VERSION 5.7 ;
  NOWIREEXTENSIONATPIN ON ;
  DIVIDERCHAR "/" ;
  BUSBITCHARS "[]" ;
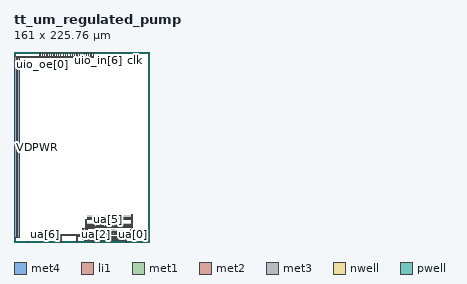
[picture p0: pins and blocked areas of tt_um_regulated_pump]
MACRO tt_um_regulated_pump
  CLASS BLOCK ;
  FOREIGN tt_um_regulated_pump ;
  ORIGIN 0.000 0.000 ;
  SIZE 161.000 BY 225.760 ;
  PIN clk
    DIRECTION INPUT ;
    USE SIGNAL ;
    PORT
      LAYER met4 ;
        RECT 143.830 224.760 144.130 225.760 ;
    END
  END clk
  PIN ena
    DIRECTION INPUT ;
    USE SIGNAL ;
    PORT
      LAYER met4 ;
        RECT 146.590 224.760 146.890 225.760 ;
    END
  END ena
  PIN rst_n
    DIRECTION INPUT ;
    USE SIGNAL ;
    PORT
      LAYER met4 ;
        RECT 141.070 224.760 141.370 225.760 ;
    END
  END rst_n
  PIN ua[0]
    DIRECTION INOUT ;
    USE SIGNAL ;
    PORT
      LAYER met4 ;
        RECT 151.810 0.000 152.710 1.000 ;
    END
  END ua[0]
  PIN ua[1]
    DIRECTION INOUT ;
    USE SIGNAL ;
    ANTENNAGATEAREA 3.960000 ;
    PORT
      LAYER li1 ;
        RECT 109.245 10.075 114.685 10.315 ;
      LAYER met1 ;
        RECT 108.300 10.315 108.740 10.410 ;
        RECT 108.300 10.065 109.540 10.315 ;
        RECT 108.300 9.970 108.740 10.065 ;
      LAYER met2 ;
        RECT 83.580 2.180 84.020 13.020 ;
        RECT 108.300 9.970 108.740 13.020 ;
        RECT 132.720 0.280 133.160 2.620 ;
      LAYER met3 ;
        RECT 83.580 12.580 108.760 13.020 ;
        RECT 83.580 2.180 133.160 2.620 ;
        RECT 132.670 0.230 133.210 0.770 ;
      LAYER met4 ;
        RECT 132.490 0.000 133.390 1.000 ;
    END
  END ua[1]
  PIN ua[2]
    DIRECTION INOUT ;
    USE SIGNAL ;
    ANTENNAGATEAREA 7.920000 ;
    PORT
      LAYER li1 ;
        RECT 88.085 10.075 93.525 10.315 ;
        RECT 98.665 10.075 104.105 10.315 ;
      LAYER met1 ;
        RECT 87.140 10.315 87.580 10.410 ;
        RECT 97.720 10.315 98.160 10.410 ;
        RECT 87.140 10.065 88.380 10.315 ;
        RECT 97.720 10.065 98.960 10.315 ;
        RECT 87.140 9.970 87.580 10.065 ;
        RECT 97.720 9.970 98.160 10.065 ;
      LAYER met2 ;
        RECT 81.580 3.380 82.020 16.220 ;
        RECT 87.140 9.970 87.580 16.220 ;
        RECT 97.720 15.780 98.180 16.220 ;
        RECT 97.720 9.970 98.160 15.780 ;
        RECT 113.400 0.280 113.840 3.820 ;
      LAYER met3 ;
        RECT 81.580 15.780 98.180 16.220 ;
        RECT 81.580 3.380 113.840 3.820 ;
        RECT 113.350 0.230 113.890 0.770 ;
      LAYER met4 ;
        RECT 113.170 0.000 114.070 1.000 ;
    END
  END ua[2]
  PIN ua[3]
    DIRECTION INOUT ;
    USE SIGNAL ;
    ANTENNADIFFAREA 3.564000 ;
    PORT
      LAYER li1 ;
        RECT 130.900 10.665 131.230 11.465 ;
        RECT 131.740 10.665 132.070 11.465 ;
        RECT 132.580 10.665 132.910 11.465 ;
        RECT 133.420 10.665 133.750 11.465 ;
        RECT 134.260 10.665 134.590 11.465 ;
        RECT 135.100 10.665 135.430 11.465 ;
        RECT 135.940 10.665 136.270 11.465 ;
        RECT 136.780 10.665 137.110 11.465 ;
        RECT 130.900 10.495 137.110 10.665 ;
        RECT 136.780 9.905 137.110 10.495 ;
        RECT 130.900 9.715 137.110 9.905 ;
        RECT 130.900 9.255 131.230 9.715 ;
        RECT 131.740 9.255 132.070 9.715 ;
        RECT 132.580 9.255 132.910 9.715 ;
        RECT 133.420 9.255 133.750 9.715 ;
        RECT 134.260 9.255 134.590 9.715 ;
        RECT 135.100 9.255 135.430 9.715 ;
        RECT 135.940 9.255 136.270 9.715 ;
        RECT 136.780 9.255 137.110 9.715 ;
      LAYER met1 ;
        RECT 138.560 10.315 139.000 10.410 ;
        RECT 136.840 10.065 139.000 10.315 ;
        RECT 138.560 9.970 139.000 10.065 ;
      LAYER met2 ;
        RECT 138.560 9.970 139.000 14.620 ;
        RECT 94.080 0.280 94.520 5.020 ;
        RECT 142.120 4.580 142.560 14.620 ;
      LAYER met3 ;
        RECT 138.540 14.180 142.560 14.620 ;
        RECT 94.080 4.580 142.560 5.020 ;
        RECT 94.030 0.230 94.570 0.770 ;
      LAYER met4 ;
        RECT 93.850 0.000 94.750 1.000 ;
    END
  END ua[3]
  PIN ua[4]
    DIRECTION INOUT ;
    USE SIGNAL ;
    ANTENNADIFFAREA 38.381248 ;
    PORT
      LAYER nwell ;
        RECT 87.810 27.785 96.010 29.390 ;
        RECT 98.390 27.785 106.590 29.390 ;
        RECT 108.970 27.785 117.170 29.390 ;
        RECT 119.550 27.785 127.750 29.390 ;
        RECT 130.130 27.785 138.330 29.390 ;
        RECT 87.810 19.045 96.010 20.650 ;
        RECT 98.390 19.045 106.590 20.650 ;
        RECT 108.970 19.045 117.170 20.650 ;
        RECT 119.550 19.045 127.750 20.650 ;
        RECT 130.130 19.045 138.330 20.650 ;
        RECT 87.810 10.305 96.010 11.910 ;
        RECT 98.390 10.305 106.590 11.910 ;
        RECT 108.970 10.305 117.170 11.910 ;
        RECT 119.550 10.305 127.750 11.910 ;
        RECT 130.130 10.305 138.330 11.910 ;
      LAYER li1 ;
        RECT 88.000 29.115 95.820 29.285 ;
        RECT 98.580 29.115 106.400 29.285 ;
        RECT 109.160 29.115 116.980 29.285 ;
        RECT 119.740 29.115 127.560 29.285 ;
        RECT 130.320 29.115 138.140 29.285 ;
        RECT 88.200 27.965 88.410 29.115 ;
        RECT 89.080 28.315 89.250 29.115 ;
        RECT 89.920 28.315 90.090 29.115 ;
        RECT 90.760 28.315 90.930 29.115 ;
        RECT 91.600 28.315 91.770 29.115 ;
        RECT 92.440 28.315 92.610 29.115 ;
        RECT 93.280 28.315 93.450 29.115 ;
        RECT 94.120 28.315 94.290 29.115 ;
        RECT 94.960 28.315 95.170 29.115 ;
        RECT 95.445 27.950 95.735 29.115 ;
        RECT 98.780 27.965 98.990 29.115 ;
        RECT 99.660 28.315 99.830 29.115 ;
        RECT 100.500 28.315 100.670 29.115 ;
        RECT 101.340 28.315 101.510 29.115 ;
        RECT 102.180 28.315 102.350 29.115 ;
        RECT 103.020 28.315 103.190 29.115 ;
        RECT 103.860 28.315 104.030 29.115 ;
        RECT 104.700 28.315 104.870 29.115 ;
        RECT 105.540 28.315 105.750 29.115 ;
        RECT 106.025 27.950 106.315 29.115 ;
        RECT 109.360 27.965 109.570 29.115 ;
        RECT 110.240 28.315 110.410 29.115 ;
        RECT 111.080 28.315 111.250 29.115 ;
        RECT 111.920 28.315 112.090 29.115 ;
        RECT 112.760 28.315 112.930 29.115 ;
        RECT 113.600 28.315 113.770 29.115 ;
        RECT 114.440 28.315 114.610 29.115 ;
        RECT 115.280 28.315 115.450 29.115 ;
        RECT 116.120 28.315 116.330 29.115 ;
        RECT 116.605 27.950 116.895 29.115 ;
        RECT 119.940 27.965 120.150 29.115 ;
        RECT 120.820 28.315 120.990 29.115 ;
        RECT 121.660 28.315 121.830 29.115 ;
        RECT 122.500 28.315 122.670 29.115 ;
        RECT 123.340 28.315 123.510 29.115 ;
        RECT 124.180 28.315 124.350 29.115 ;
        RECT 125.020 28.315 125.190 29.115 ;
        RECT 125.860 28.315 126.030 29.115 ;
        RECT 126.700 28.315 126.910 29.115 ;
        RECT 127.185 27.950 127.475 29.115 ;
        RECT 130.520 27.965 130.730 29.115 ;
        RECT 131.400 28.315 131.570 29.115 ;
        RECT 132.240 28.315 132.410 29.115 ;
        RECT 133.080 28.315 133.250 29.115 ;
        RECT 133.920 28.315 134.090 29.115 ;
        RECT 134.760 28.315 134.930 29.115 ;
        RECT 135.600 28.315 135.770 29.115 ;
        RECT 136.440 28.315 136.610 29.115 ;
        RECT 137.280 28.315 137.490 29.115 ;
        RECT 137.765 27.950 138.055 29.115 ;
        RECT 88.000 20.375 95.820 20.545 ;
        RECT 98.580 20.375 106.400 20.545 ;
        RECT 109.160 20.375 116.980 20.545 ;
        RECT 119.740 20.375 127.560 20.545 ;
        RECT 130.320 20.375 138.140 20.545 ;
        RECT 88.200 19.225 88.410 20.375 ;
        RECT 89.080 19.575 89.250 20.375 ;
        RECT 89.920 19.575 90.090 20.375 ;
        RECT 90.760 19.575 90.930 20.375 ;
        RECT 91.600 19.575 91.770 20.375 ;
        RECT 92.440 19.575 92.610 20.375 ;
        RECT 93.280 19.575 93.450 20.375 ;
        RECT 94.120 19.575 94.290 20.375 ;
        RECT 94.960 19.575 95.170 20.375 ;
        RECT 95.445 19.210 95.735 20.375 ;
        RECT 98.780 19.225 98.990 20.375 ;
        RECT 99.660 19.575 99.830 20.375 ;
        RECT 100.500 19.575 100.670 20.375 ;
        RECT 101.340 19.575 101.510 20.375 ;
        RECT 102.180 19.575 102.350 20.375 ;
        RECT 103.020 19.575 103.190 20.375 ;
        RECT 103.860 19.575 104.030 20.375 ;
        RECT 104.700 19.575 104.870 20.375 ;
        RECT 105.540 19.575 105.750 20.375 ;
        RECT 106.025 19.210 106.315 20.375 ;
        RECT 109.360 19.225 109.570 20.375 ;
        RECT 110.240 19.575 110.410 20.375 ;
        RECT 111.080 19.575 111.250 20.375 ;
        RECT 111.920 19.575 112.090 20.375 ;
        RECT 112.760 19.575 112.930 20.375 ;
        RECT 113.600 19.575 113.770 20.375 ;
        RECT 114.440 19.575 114.610 20.375 ;
        RECT 115.280 19.575 115.450 20.375 ;
        RECT 116.120 19.575 116.330 20.375 ;
        RECT 116.605 19.210 116.895 20.375 ;
        RECT 119.940 19.225 120.150 20.375 ;
        RECT 120.820 19.575 120.990 20.375 ;
        RECT 121.660 19.575 121.830 20.375 ;
        RECT 122.500 19.575 122.670 20.375 ;
        RECT 123.340 19.575 123.510 20.375 ;
        RECT 124.180 19.575 124.350 20.375 ;
        RECT 125.020 19.575 125.190 20.375 ;
        RECT 125.860 19.575 126.030 20.375 ;
        RECT 126.700 19.575 126.910 20.375 ;
        RECT 127.185 19.210 127.475 20.375 ;
        RECT 130.520 19.225 130.730 20.375 ;
        RECT 131.400 19.575 131.570 20.375 ;
        RECT 132.240 19.575 132.410 20.375 ;
        RECT 133.080 19.575 133.250 20.375 ;
        RECT 133.920 19.575 134.090 20.375 ;
        RECT 134.760 19.575 134.930 20.375 ;
        RECT 135.600 19.575 135.770 20.375 ;
        RECT 136.440 19.575 136.610 20.375 ;
        RECT 137.280 19.575 137.490 20.375 ;
        RECT 137.765 19.210 138.055 20.375 ;
        RECT 88.000 11.635 95.820 11.805 ;
        RECT 98.580 11.635 106.400 11.805 ;
        RECT 109.160 11.635 116.980 11.805 ;
        RECT 119.740 11.635 127.560 11.805 ;
        RECT 130.320 11.635 138.140 11.805 ;
        RECT 88.200 10.485 88.410 11.635 ;
        RECT 89.080 10.835 89.250 11.635 ;
        RECT 89.920 10.835 90.090 11.635 ;
        RECT 90.760 10.835 90.930 11.635 ;
        RECT 91.600 10.835 91.770 11.635 ;
        RECT 92.440 10.835 92.610 11.635 ;
        RECT 93.280 10.835 93.450 11.635 ;
        RECT 94.120 10.835 94.290 11.635 ;
        RECT 94.960 10.835 95.170 11.635 ;
        RECT 95.445 10.470 95.735 11.635 ;
        RECT 98.780 10.485 98.990 11.635 ;
        RECT 99.660 10.835 99.830 11.635 ;
        RECT 100.500 10.835 100.670 11.635 ;
        RECT 101.340 10.835 101.510 11.635 ;
        RECT 102.180 10.835 102.350 11.635 ;
        RECT 103.020 10.835 103.190 11.635 ;
        RECT 103.860 10.835 104.030 11.635 ;
        RECT 104.700 10.835 104.870 11.635 ;
        RECT 105.540 10.835 105.750 11.635 ;
        RECT 106.025 10.470 106.315 11.635 ;
        RECT 109.360 10.485 109.570 11.635 ;
        RECT 110.240 10.835 110.410 11.635 ;
        RECT 111.080 10.835 111.250 11.635 ;
        RECT 111.920 10.835 112.090 11.635 ;
        RECT 112.760 10.835 112.930 11.635 ;
        RECT 113.600 10.835 113.770 11.635 ;
        RECT 114.440 10.835 114.610 11.635 ;
        RECT 115.280 10.835 115.450 11.635 ;
        RECT 116.120 10.835 116.330 11.635 ;
        RECT 116.605 10.470 116.895 11.635 ;
        RECT 119.940 10.485 120.150 11.635 ;
        RECT 120.820 10.835 120.990 11.635 ;
        RECT 121.660 10.835 121.830 11.635 ;
        RECT 122.500 10.835 122.670 11.635 ;
        RECT 123.340 10.835 123.510 11.635 ;
        RECT 124.180 10.835 124.350 11.635 ;
        RECT 125.020 10.835 125.190 11.635 ;
        RECT 125.860 10.835 126.030 11.635 ;
        RECT 126.700 10.835 126.910 11.635 ;
        RECT 127.185 10.470 127.475 11.635 ;
        RECT 130.520 10.485 130.730 11.635 ;
        RECT 131.400 10.835 131.570 11.635 ;
        RECT 132.240 10.835 132.410 11.635 ;
        RECT 133.080 10.835 133.250 11.635 ;
        RECT 133.920 10.835 134.090 11.635 ;
        RECT 134.760 10.835 134.930 11.635 ;
        RECT 135.600 10.835 135.770 11.635 ;
        RECT 136.440 10.835 136.610 11.635 ;
        RECT 137.280 10.835 137.490 11.635 ;
        RECT 137.765 10.470 138.055 11.635 ;
      LAYER met1 ;
        RECT 88.000 28.960 140.840 29.440 ;
        RECT 88.000 20.220 140.840 20.700 ;
        RECT 88.000 11.480 140.840 11.960 ;
      LAYER met2 ;
        RECT 139.840 11.480 140.840 32.320 ;
        RECT 140.090 6.250 140.590 11.480 ;
      LAYER met3 ;
        RECT 74.730 6.250 140.590 6.750 ;
        RECT 74.730 0.250 75.230 6.250 ;
      LAYER met4 ;
        RECT 74.530 0.000 75.430 1.000 ;
    END
  END ua[4]
  PIN ua[5]
    DIRECTION INOUT ;
    USE SIGNAL ;
    ANTENNADIFFAREA 24.836250 ;
    PORT
      LAYER pwell ;
        RECT 95.375 26.670 95.805 27.455 ;
        RECT 105.955 26.670 106.385 27.455 ;
        RECT 116.535 26.670 116.965 27.455 ;
        RECT 127.115 26.670 127.545 27.455 ;
        RECT 137.695 26.670 138.125 27.455 ;
        RECT 95.375 17.930 95.805 18.715 ;
        RECT 105.955 17.930 106.385 18.715 ;
        RECT 116.535 17.930 116.965 18.715 ;
        RECT 127.115 17.930 127.545 18.715 ;
        RECT 137.695 17.930 138.125 18.715 ;
        RECT 95.375 9.190 95.805 9.975 ;
        RECT 105.955 9.190 106.385 9.975 ;
        RECT 116.535 9.190 116.965 9.975 ;
        RECT 127.115 9.190 127.545 9.975 ;
        RECT 137.695 9.190 138.125 9.975 ;
      LAYER li1 ;
        RECT 88.180 26.565 88.410 27.365 ;
        RECT 89.080 26.565 89.250 27.025 ;
        RECT 89.920 26.565 90.090 27.025 ;
        RECT 90.760 26.565 90.930 27.025 ;
        RECT 91.600 26.565 91.770 27.025 ;
        RECT 92.440 26.565 92.610 27.025 ;
        RECT 93.280 26.565 93.450 27.025 ;
        RECT 94.120 26.565 94.290 27.025 ;
        RECT 94.960 26.565 95.170 27.365 ;
        RECT 95.445 26.565 95.735 27.290 ;
        RECT 98.760 26.565 98.990 27.365 ;
        RECT 99.660 26.565 99.830 27.025 ;
        RECT 100.500 26.565 100.670 27.025 ;
        RECT 101.340 26.565 101.510 27.025 ;
        RECT 102.180 26.565 102.350 27.025 ;
        RECT 103.020 26.565 103.190 27.025 ;
        RECT 103.860 26.565 104.030 27.025 ;
        RECT 104.700 26.565 104.870 27.025 ;
        RECT 105.540 26.565 105.750 27.365 ;
        RECT 106.025 26.565 106.315 27.290 ;
        RECT 109.340 26.565 109.570 27.365 ;
        RECT 110.240 26.565 110.410 27.025 ;
        RECT 111.080 26.565 111.250 27.025 ;
        RECT 111.920 26.565 112.090 27.025 ;
        RECT 112.760 26.565 112.930 27.025 ;
        RECT 113.600 26.565 113.770 27.025 ;
        RECT 114.440 26.565 114.610 27.025 ;
        RECT 115.280 26.565 115.450 27.025 ;
        RECT 116.120 26.565 116.330 27.365 ;
        RECT 116.605 26.565 116.895 27.290 ;
        RECT 119.920 26.565 120.150 27.365 ;
        RECT 120.820 26.565 120.990 27.025 ;
        RECT 121.660 26.565 121.830 27.025 ;
        RECT 122.500 26.565 122.670 27.025 ;
        RECT 123.340 26.565 123.510 27.025 ;
        RECT 124.180 26.565 124.350 27.025 ;
        RECT 125.020 26.565 125.190 27.025 ;
        RECT 125.860 26.565 126.030 27.025 ;
        RECT 126.700 26.565 126.910 27.365 ;
        RECT 127.185 26.565 127.475 27.290 ;
        RECT 130.500 26.565 130.730 27.365 ;
        RECT 131.400 26.565 131.570 27.025 ;
        RECT 132.240 26.565 132.410 27.025 ;
        RECT 133.080 26.565 133.250 27.025 ;
        RECT 133.920 26.565 134.090 27.025 ;
        RECT 134.760 26.565 134.930 27.025 ;
        RECT 135.600 26.565 135.770 27.025 ;
        RECT 136.440 26.565 136.610 27.025 ;
        RECT 137.280 26.565 137.490 27.365 ;
        RECT 137.765 26.565 138.055 27.290 ;
        RECT 88.000 26.395 95.820 26.565 ;
        RECT 98.580 26.395 106.400 26.565 ;
        RECT 109.160 26.395 116.980 26.565 ;
        RECT 119.740 26.395 127.560 26.565 ;
        RECT 130.320 26.395 138.140 26.565 ;
        RECT 88.180 17.825 88.410 18.625 ;
        RECT 89.080 17.825 89.250 18.285 ;
        RECT 89.920 17.825 90.090 18.285 ;
        RECT 90.760 17.825 90.930 18.285 ;
        RECT 91.600 17.825 91.770 18.285 ;
        RECT 92.440 17.825 92.610 18.285 ;
        RECT 93.280 17.825 93.450 18.285 ;
        RECT 94.120 17.825 94.290 18.285 ;
        RECT 94.960 17.825 95.170 18.625 ;
        RECT 95.445 17.825 95.735 18.550 ;
        RECT 98.760 17.825 98.990 18.625 ;
        RECT 99.660 17.825 99.830 18.285 ;
        RECT 100.500 17.825 100.670 18.285 ;
        RECT 101.340 17.825 101.510 18.285 ;
        RECT 102.180 17.825 102.350 18.285 ;
        RECT 103.020 17.825 103.190 18.285 ;
        RECT 103.860 17.825 104.030 18.285 ;
        RECT 104.700 17.825 104.870 18.285 ;
        RECT 105.540 17.825 105.750 18.625 ;
        RECT 106.025 17.825 106.315 18.550 ;
        RECT 109.340 17.825 109.570 18.625 ;
        RECT 110.240 17.825 110.410 18.285 ;
        RECT 111.080 17.825 111.250 18.285 ;
        RECT 111.920 17.825 112.090 18.285 ;
        RECT 112.760 17.825 112.930 18.285 ;
        RECT 113.600 17.825 113.770 18.285 ;
        RECT 114.440 17.825 114.610 18.285 ;
        RECT 115.280 17.825 115.450 18.285 ;
        RECT 116.120 17.825 116.330 18.625 ;
        RECT 116.605 17.825 116.895 18.550 ;
        RECT 119.920 17.825 120.150 18.625 ;
        RECT 120.820 17.825 120.990 18.285 ;
        RECT 121.660 17.825 121.830 18.285 ;
        RECT 122.500 17.825 122.670 18.285 ;
        RECT 123.340 17.825 123.510 18.285 ;
        RECT 124.180 17.825 124.350 18.285 ;
        RECT 125.020 17.825 125.190 18.285 ;
        RECT 125.860 17.825 126.030 18.285 ;
        RECT 126.700 17.825 126.910 18.625 ;
        RECT 127.185 17.825 127.475 18.550 ;
        RECT 130.500 17.825 130.730 18.625 ;
        RECT 131.400 17.825 131.570 18.285 ;
        RECT 132.240 17.825 132.410 18.285 ;
        RECT 133.080 17.825 133.250 18.285 ;
        RECT 133.920 17.825 134.090 18.285 ;
        RECT 134.760 17.825 134.930 18.285 ;
        RECT 135.600 17.825 135.770 18.285 ;
        RECT 136.440 17.825 136.610 18.285 ;
        RECT 137.280 17.825 137.490 18.625 ;
        RECT 137.765 17.825 138.055 18.550 ;
        RECT 88.000 17.655 95.820 17.825 ;
        RECT 98.580 17.655 106.400 17.825 ;
        RECT 109.160 17.655 116.980 17.825 ;
        RECT 119.740 17.655 127.560 17.825 ;
        RECT 130.320 17.655 138.140 17.825 ;
        RECT 88.180 9.085 88.410 9.885 ;
        RECT 89.080 9.085 89.250 9.545 ;
        RECT 89.920 9.085 90.090 9.545 ;
        RECT 90.760 9.085 90.930 9.545 ;
        RECT 91.600 9.085 91.770 9.545 ;
        RECT 92.440 9.085 92.610 9.545 ;
        RECT 93.280 9.085 93.450 9.545 ;
        RECT 94.120 9.085 94.290 9.545 ;
        RECT 94.960 9.085 95.170 9.885 ;
        RECT 95.445 9.085 95.735 9.810 ;
        RECT 98.760 9.085 98.990 9.885 ;
        RECT 99.660 9.085 99.830 9.545 ;
        RECT 100.500 9.085 100.670 9.545 ;
        RECT 101.340 9.085 101.510 9.545 ;
        RECT 102.180 9.085 102.350 9.545 ;
        RECT 103.020 9.085 103.190 9.545 ;
        RECT 103.860 9.085 104.030 9.545 ;
        RECT 104.700 9.085 104.870 9.545 ;
        RECT 105.540 9.085 105.750 9.885 ;
        RECT 106.025 9.085 106.315 9.810 ;
        RECT 109.340 9.085 109.570 9.885 ;
        RECT 110.240 9.085 110.410 9.545 ;
        RECT 111.080 9.085 111.250 9.545 ;
        RECT 111.920 9.085 112.090 9.545 ;
        RECT 112.760 9.085 112.930 9.545 ;
        RECT 113.600 9.085 113.770 9.545 ;
        RECT 114.440 9.085 114.610 9.545 ;
        RECT 115.280 9.085 115.450 9.545 ;
        RECT 116.120 9.085 116.330 9.885 ;
        RECT 116.605 9.085 116.895 9.810 ;
        RECT 119.920 9.085 120.150 9.885 ;
        RECT 120.820 9.085 120.990 9.545 ;
        RECT 121.660 9.085 121.830 9.545 ;
        RECT 122.500 9.085 122.670 9.545 ;
        RECT 123.340 9.085 123.510 9.545 ;
        RECT 124.180 9.085 124.350 9.545 ;
        RECT 125.020 9.085 125.190 9.545 ;
        RECT 125.860 9.085 126.030 9.545 ;
        RECT 126.700 9.085 126.910 9.885 ;
        RECT 127.185 9.085 127.475 9.810 ;
        RECT 130.500 9.085 130.730 9.885 ;
        RECT 131.400 9.085 131.570 9.545 ;
        RECT 132.240 9.085 132.410 9.545 ;
        RECT 133.080 9.085 133.250 9.545 ;
        RECT 133.920 9.085 134.090 9.545 ;
        RECT 134.760 9.085 134.930 9.545 ;
        RECT 135.600 9.085 135.770 9.545 ;
        RECT 136.440 9.085 136.610 9.545 ;
        RECT 137.280 9.085 137.490 9.885 ;
        RECT 137.765 9.085 138.055 9.810 ;
        RECT 88.000 8.915 95.820 9.085 ;
        RECT 98.580 8.915 106.400 9.085 ;
        RECT 109.160 8.915 116.980 9.085 ;
        RECT 119.740 8.915 127.560 9.085 ;
        RECT 130.320 8.915 138.140 9.085 ;
      LAYER met1 ;
        RECT 85.300 26.240 138.140 26.720 ;
        RECT 85.300 17.500 138.140 17.980 ;
        RECT 85.300 8.760 138.140 9.240 ;
      LAYER met2 ;
        RECT 85.300 8.260 86.300 26.720 ;
        RECT 85.550 8.250 86.050 8.260 ;
      LAYER met3 ;
        RECT 55.410 8.250 86.050 8.750 ;
        RECT 55.410 0.250 55.910 8.250 ;
      LAYER met4 ;
        RECT 55.210 0.000 56.110 1.000 ;
    END
  END ua[5]
  PIN ua[6]
    DIRECTION INOUT ;
    USE SIGNAL ;
    PORT
      LAYER met4 ;
        RECT 35.890 0.000 36.790 1.000 ;
    END
  END ua[6]
  PIN ua[7]
    DIRECTION INOUT ;
    USE SIGNAL ;
    PORT
      LAYER met4 ;
        RECT 16.570 0.000 17.470 1.000 ;
    END
  END ua[7]
  PIN ui_in[0]
    DIRECTION INPUT ;
    USE SIGNAL ;
    PORT
      LAYER met4 ;
        RECT 138.310 224.760 138.610 225.760 ;
    END
  END ui_in[0]
  PIN ui_in[1]
    DIRECTION INPUT ;
    USE SIGNAL ;
    PORT
      LAYER met4 ;
        RECT 135.550 224.760 135.850 225.760 ;
    END
  END ui_in[1]
  PIN ui_in[2]
    DIRECTION INPUT ;
    USE SIGNAL ;
    PORT
      LAYER met4 ;
        RECT 132.790 224.760 133.090 225.760 ;
    END
  END ui_in[2]
  PIN ui_in[3]
    DIRECTION INPUT ;
    USE SIGNAL ;
    PORT
      LAYER met4 ;
        RECT 130.030 224.760 130.330 225.760 ;
    END
  END ui_in[3]
  PIN ui_in[4]
    DIRECTION INPUT ;
    USE SIGNAL ;
    PORT
      LAYER met4 ;
        RECT 127.270 224.760 127.570 225.760 ;
    END
  END ui_in[4]
  PIN ui_in[5]
    DIRECTION INPUT ;
    USE SIGNAL ;
    PORT
      LAYER met4 ;
        RECT 124.510 224.760 124.810 225.760 ;
    END
  END ui_in[5]
  PIN ui_in[6]
    DIRECTION INPUT ;
    USE SIGNAL ;
    PORT
      LAYER met4 ;
        RECT 121.750 224.760 122.050 225.760 ;
    END
  END ui_in[6]
  PIN ui_in[7]
    DIRECTION INPUT ;
    USE SIGNAL ;
    PORT
      LAYER met4 ;
        RECT 118.990 224.760 119.290 225.760 ;
    END
  END ui_in[7]
  PIN uio_in[0]
    DIRECTION INPUT ;
    USE SIGNAL ;
    PORT
      LAYER met4 ;
        RECT 116.230 224.760 116.530 225.760 ;
    END
  END uio_in[0]
  PIN uio_in[1]
    DIRECTION INPUT ;
    USE SIGNAL ;
    PORT
      LAYER met4 ;
        RECT 113.470 224.760 113.770 225.760 ;
    END
  END uio_in[1]
  PIN uio_in[2]
    DIRECTION INPUT ;
    USE SIGNAL ;
    PORT
      LAYER met4 ;
        RECT 110.710 224.760 111.010 225.760 ;
    END
  END uio_in[2]
  PIN uio_in[3]
    DIRECTION INPUT ;
    USE SIGNAL ;
    PORT
      LAYER met4 ;
        RECT 107.950 224.760 108.250 225.760 ;
    END
  END uio_in[3]
  PIN uio_in[4]
    DIRECTION INPUT ;
    USE SIGNAL ;
    PORT
      LAYER met4 ;
        RECT 105.190 224.760 105.490 225.760 ;
    END
  END uio_in[4]
  PIN uio_in[5]
    DIRECTION INPUT ;
    USE SIGNAL ;
    PORT
      LAYER met4 ;
        RECT 102.430 224.760 102.730 225.760 ;
    END
  END uio_in[5]
  PIN uio_in[6]
    DIRECTION INPUT ;
    USE SIGNAL ;
    PORT
      LAYER met4 ;
        RECT 99.670 224.760 99.970 225.760 ;
    END
  END uio_in[6]
  PIN uio_in[7]
    DIRECTION INPUT ;
    USE SIGNAL ;
    PORT
      LAYER met4 ;
        RECT 96.910 224.760 97.210 225.760 ;
    END
  END uio_in[7]
  PIN uio_oe[0]
    DIRECTION OUTPUT ;
    USE SIGNAL ;
    PORT
      LAYER met3 ;
        RECT 4.770 219.770 94.530 220.230 ;
      LAYER met4 ;
        RECT 4.000 5.000 6.000 220.760 ;
        RECT 30.670 220.230 30.970 225.760 ;
        RECT 33.430 220.230 33.730 225.760 ;
        RECT 36.190 220.230 36.490 225.760 ;
        RECT 38.950 220.230 39.250 225.760 ;
        RECT 41.710 220.230 42.010 225.760 ;
        RECT 44.470 220.230 44.770 225.760 ;
        RECT 47.230 220.230 47.530 225.760 ;
        RECT 49.990 220.230 50.290 225.760 ;
        RECT 52.750 220.230 53.050 225.760 ;
        RECT 55.510 220.230 55.810 225.760 ;
        RECT 58.270 220.230 58.570 225.760 ;
        RECT 61.030 220.230 61.330 225.760 ;
        RECT 63.790 220.230 64.090 225.760 ;
        RECT 66.550 220.230 66.850 225.760 ;
        RECT 69.310 220.230 69.610 225.760 ;
        RECT 72.070 220.230 72.370 225.760 ;
        RECT 74.830 220.230 75.130 225.760 ;
        RECT 77.590 220.230 77.890 225.760 ;
        RECT 80.350 220.230 80.650 225.760 ;
        RECT 83.110 220.230 83.410 225.760 ;
        RECT 85.870 220.230 86.170 225.760 ;
        RECT 88.630 220.230 88.930 225.760 ;
        RECT 91.390 220.230 91.690 225.760 ;
        RECT 94.150 220.230 94.450 225.760 ;
        RECT 30.590 219.770 31.050 220.230 ;
        RECT 33.350 219.770 33.810 220.230 ;
        RECT 36.110 219.770 36.570 220.230 ;
        RECT 38.870 219.770 39.330 220.230 ;
        RECT 41.630 219.770 42.090 220.230 ;
        RECT 44.390 219.770 44.850 220.230 ;
        RECT 47.150 219.770 47.610 220.230 ;
        RECT 49.910 219.770 50.370 220.230 ;
        RECT 52.670 219.770 53.130 220.230 ;
        RECT 55.430 219.770 55.890 220.230 ;
        RECT 58.190 219.770 58.650 220.230 ;
        RECT 60.950 219.770 61.410 220.230 ;
        RECT 63.710 219.770 64.170 220.230 ;
        RECT 66.470 219.770 66.930 220.230 ;
        RECT 69.230 219.770 69.690 220.230 ;
        RECT 71.990 219.770 72.450 220.230 ;
        RECT 74.750 219.770 75.210 220.230 ;
        RECT 77.510 219.770 77.970 220.230 ;
        RECT 80.270 219.770 80.730 220.230 ;
        RECT 83.030 219.770 83.490 220.230 ;
        RECT 85.790 219.770 86.250 220.230 ;
        RECT 88.550 219.770 89.010 220.230 ;
        RECT 91.310 219.770 91.770 220.230 ;
        RECT 94.070 219.770 94.530 220.230 ;
    END
  END uio_oe[0]
  PIN VDPWR
    DIRECTION INOUT ;
    USE POWER ;
    PORT
      LAYER met4 ;
        RECT 1.000 5.000 3.000 220.760 ;
    END
  END VDPWR
  OBS
      LAYER pwell ;
        RECT 88.070 26.585 95.300 27.495 ;
        RECT 98.650 26.585 105.880 27.495 ;
        RECT 109.230 26.585 116.460 27.495 ;
        RECT 119.810 26.585 127.040 27.495 ;
        RECT 130.390 26.585 137.620 27.495 ;
        RECT 88.145 26.395 88.315 26.585 ;
        RECT 98.725 26.395 98.895 26.585 ;
        RECT 109.305 26.395 109.475 26.585 ;
        RECT 119.885 26.395 120.055 26.585 ;
        RECT 130.465 26.395 130.635 26.585 ;
        RECT 88.070 17.845 95.300 18.755 ;
        RECT 98.650 17.845 105.880 18.755 ;
        RECT 109.230 17.845 116.460 18.755 ;
        RECT 119.810 17.845 127.040 18.755 ;
        RECT 130.390 17.845 137.620 18.755 ;
        RECT 88.145 17.655 88.315 17.845 ;
        RECT 98.725 17.655 98.895 17.845 ;
        RECT 109.305 17.655 109.475 17.845 ;
        RECT 119.885 17.655 120.055 17.845 ;
        RECT 130.465 17.655 130.635 17.845 ;
        RECT 88.070 9.105 95.300 10.015 ;
        RECT 98.650 9.105 105.880 10.015 ;
        RECT 109.230 9.105 116.460 10.015 ;
        RECT 119.810 9.105 127.040 10.015 ;
        RECT 130.390 9.105 137.620 10.015 ;
        RECT 88.145 8.915 88.315 9.105 ;
        RECT 98.725 8.915 98.895 9.105 ;
        RECT 109.305 8.915 109.475 9.105 ;
        RECT 119.885 8.915 120.055 9.105 ;
        RECT 130.465 8.915 130.635 9.105 ;
      LAYER li1 ;
        RECT 88.580 28.145 88.910 28.945 ;
        RECT 89.420 28.145 89.750 28.945 ;
        RECT 90.260 28.145 90.590 28.945 ;
        RECT 91.100 28.145 91.430 28.945 ;
        RECT 91.940 28.145 92.270 28.945 ;
        RECT 92.780 28.145 93.110 28.945 ;
        RECT 93.620 28.145 93.950 28.945 ;
        RECT 94.460 28.145 94.790 28.945 ;
        RECT 88.580 27.975 94.790 28.145 ;
        RECT 99.160 28.145 99.490 28.945 ;
        RECT 100.000 28.145 100.330 28.945 ;
        RECT 100.840 28.145 101.170 28.945 ;
        RECT 101.680 28.145 102.010 28.945 ;
        RECT 102.520 28.145 102.850 28.945 ;
        RECT 103.360 28.145 103.690 28.945 ;
        RECT 104.200 28.145 104.530 28.945 ;
        RECT 105.040 28.145 105.370 28.945 ;
        RECT 99.160 27.975 105.370 28.145 ;
        RECT 109.740 28.145 110.070 28.945 ;
        RECT 110.580 28.145 110.910 28.945 ;
        RECT 111.420 28.145 111.750 28.945 ;
        RECT 112.260 28.145 112.590 28.945 ;
        RECT 113.100 28.145 113.430 28.945 ;
        RECT 113.940 28.145 114.270 28.945 ;
        RECT 114.780 28.145 115.110 28.945 ;
        RECT 115.620 28.145 115.950 28.945 ;
        RECT 109.740 27.975 115.950 28.145 ;
        RECT 120.320 28.145 120.650 28.945 ;
        RECT 121.160 28.145 121.490 28.945 ;
        RECT 122.000 28.145 122.330 28.945 ;
        RECT 122.840 28.145 123.170 28.945 ;
        RECT 123.680 28.145 124.010 28.945 ;
        RECT 124.520 28.145 124.850 28.945 ;
        RECT 125.360 28.145 125.690 28.945 ;
        RECT 126.200 28.145 126.530 28.945 ;
        RECT 120.320 27.975 126.530 28.145 ;
        RECT 130.900 28.145 131.230 28.945 ;
        RECT 131.740 28.145 132.070 28.945 ;
        RECT 132.580 28.145 132.910 28.945 ;
        RECT 133.420 28.145 133.750 28.945 ;
        RECT 134.260 28.145 134.590 28.945 ;
        RECT 135.100 28.145 135.430 28.945 ;
        RECT 135.940 28.145 136.270 28.945 ;
        RECT 136.780 28.145 137.110 28.945 ;
        RECT 130.900 27.975 137.110 28.145 ;
        RECT 88.085 27.555 93.525 27.795 ;
        RECT 94.460 27.385 94.790 27.975 ;
        RECT 98.665 27.555 104.105 27.795 ;
        RECT 105.040 27.385 105.370 27.975 ;
        RECT 109.245 27.555 114.685 27.795 ;
        RECT 115.620 27.385 115.950 27.975 ;
        RECT 119.825 27.555 125.265 27.795 ;
        RECT 126.200 27.385 126.530 27.975 ;
        RECT 130.405 27.555 135.845 27.795 ;
        RECT 136.780 27.385 137.110 27.975 ;
        RECT 88.580 27.195 94.790 27.385 ;
        RECT 88.580 26.735 88.910 27.195 ;
        RECT 89.420 26.735 89.750 27.195 ;
        RECT 90.260 26.735 90.590 27.195 ;
        RECT 91.100 26.735 91.430 27.195 ;
        RECT 91.940 26.735 92.270 27.195 ;
        RECT 92.780 26.735 93.110 27.195 ;
        RECT 93.620 26.735 93.950 27.195 ;
        RECT 94.460 26.735 94.790 27.195 ;
        RECT 99.160 27.195 105.370 27.385 ;
        RECT 99.160 26.735 99.490 27.195 ;
        RECT 100.000 26.735 100.330 27.195 ;
        RECT 100.840 26.735 101.170 27.195 ;
        RECT 101.680 26.735 102.010 27.195 ;
        RECT 102.520 26.735 102.850 27.195 ;
        RECT 103.360 26.735 103.690 27.195 ;
        RECT 104.200 26.735 104.530 27.195 ;
        RECT 105.040 26.735 105.370 27.195 ;
        RECT 109.740 27.195 115.950 27.385 ;
        RECT 109.740 26.735 110.070 27.195 ;
        RECT 110.580 26.735 110.910 27.195 ;
        RECT 111.420 26.735 111.750 27.195 ;
        RECT 112.260 26.735 112.590 27.195 ;
        RECT 113.100 26.735 113.430 27.195 ;
        RECT 113.940 26.735 114.270 27.195 ;
        RECT 114.780 26.735 115.110 27.195 ;
        RECT 115.620 26.735 115.950 27.195 ;
        RECT 120.320 27.195 126.530 27.385 ;
        RECT 120.320 26.735 120.650 27.195 ;
        RECT 121.160 26.735 121.490 27.195 ;
        RECT 122.000 26.735 122.330 27.195 ;
        RECT 122.840 26.735 123.170 27.195 ;
        RECT 123.680 26.735 124.010 27.195 ;
        RECT 124.520 26.735 124.850 27.195 ;
        RECT 125.360 26.735 125.690 27.195 ;
        RECT 126.200 26.735 126.530 27.195 ;
        RECT 130.900 27.195 137.110 27.385 ;
        RECT 130.900 26.735 131.230 27.195 ;
        RECT 131.740 26.735 132.070 27.195 ;
        RECT 132.580 26.735 132.910 27.195 ;
        RECT 133.420 26.735 133.750 27.195 ;
        RECT 134.260 26.735 134.590 27.195 ;
        RECT 135.100 26.735 135.430 27.195 ;
        RECT 135.940 26.735 136.270 27.195 ;
        RECT 136.780 26.735 137.110 27.195 ;
        RECT 88.580 19.405 88.910 20.205 ;
        RECT 89.420 19.405 89.750 20.205 ;
        RECT 90.260 19.405 90.590 20.205 ;
        RECT 91.100 19.405 91.430 20.205 ;
        RECT 91.940 19.405 92.270 20.205 ;
        RECT 92.780 19.405 93.110 20.205 ;
        RECT 93.620 19.405 93.950 20.205 ;
        RECT 94.460 19.405 94.790 20.205 ;
        RECT 88.580 19.235 94.790 19.405 ;
        RECT 99.160 19.405 99.490 20.205 ;
        RECT 100.000 19.405 100.330 20.205 ;
        RECT 100.840 19.405 101.170 20.205 ;
        RECT 101.680 19.405 102.010 20.205 ;
        RECT 102.520 19.405 102.850 20.205 ;
        RECT 103.360 19.405 103.690 20.205 ;
        RECT 104.200 19.405 104.530 20.205 ;
        RECT 105.040 19.405 105.370 20.205 ;
        RECT 99.160 19.235 105.370 19.405 ;
        RECT 109.740 19.405 110.070 20.205 ;
        RECT 110.580 19.405 110.910 20.205 ;
        RECT 111.420 19.405 111.750 20.205 ;
        RECT 112.260 19.405 112.590 20.205 ;
        RECT 113.100 19.405 113.430 20.205 ;
        RECT 113.940 19.405 114.270 20.205 ;
        RECT 114.780 19.405 115.110 20.205 ;
        RECT 115.620 19.405 115.950 20.205 ;
        RECT 109.740 19.235 115.950 19.405 ;
        RECT 120.320 19.405 120.650 20.205 ;
        RECT 121.160 19.405 121.490 20.205 ;
        RECT 122.000 19.405 122.330 20.205 ;
        RECT 122.840 19.405 123.170 20.205 ;
        RECT 123.680 19.405 124.010 20.205 ;
        RECT 124.520 19.405 124.850 20.205 ;
        RECT 125.360 19.405 125.690 20.205 ;
        RECT 126.200 19.405 126.530 20.205 ;
        RECT 120.320 19.235 126.530 19.405 ;
        RECT 130.900 19.405 131.230 20.205 ;
        RECT 131.740 19.405 132.070 20.205 ;
        RECT 132.580 19.405 132.910 20.205 ;
        RECT 133.420 19.405 133.750 20.205 ;
        RECT 134.260 19.405 134.590 20.205 ;
        RECT 135.100 19.405 135.430 20.205 ;
        RECT 135.940 19.405 136.270 20.205 ;
        RECT 136.780 19.405 137.110 20.205 ;
        RECT 130.900 19.235 137.110 19.405 ;
        RECT 88.085 18.815 93.525 19.055 ;
        RECT 94.460 18.645 94.790 19.235 ;
        RECT 98.665 18.815 104.105 19.055 ;
        RECT 105.040 18.645 105.370 19.235 ;
        RECT 109.245 18.815 114.685 19.055 ;
        RECT 115.620 18.645 115.950 19.235 ;
        RECT 119.825 18.815 125.265 19.055 ;
        RECT 126.200 18.645 126.530 19.235 ;
        RECT 130.405 18.815 135.845 19.055 ;
        RECT 136.780 18.645 137.110 19.235 ;
        RECT 88.580 18.455 94.790 18.645 ;
        RECT 88.580 17.995 88.910 18.455 ;
        RECT 89.420 17.995 89.750 18.455 ;
        RECT 90.260 17.995 90.590 18.455 ;
        RECT 91.100 17.995 91.430 18.455 ;
        RECT 91.940 17.995 92.270 18.455 ;
        RECT 92.780 17.995 93.110 18.455 ;
        RECT 93.620 17.995 93.950 18.455 ;
        RECT 94.460 17.995 94.790 18.455 ;
        RECT 99.160 18.455 105.370 18.645 ;
        RECT 99.160 17.995 99.490 18.455 ;
        RECT 100.000 17.995 100.330 18.455 ;
        RECT 100.840 17.995 101.170 18.455 ;
        RECT 101.680 17.995 102.010 18.455 ;
        RECT 102.520 17.995 102.850 18.455 ;
        RECT 103.360 17.995 103.690 18.455 ;
        RECT 104.200 17.995 104.530 18.455 ;
        RECT 105.040 17.995 105.370 18.455 ;
        RECT 109.740 18.455 115.950 18.645 ;
        RECT 109.740 17.995 110.070 18.455 ;
        RECT 110.580 17.995 110.910 18.455 ;
        RECT 111.420 17.995 111.750 18.455 ;
        RECT 112.260 17.995 112.590 18.455 ;
        RECT 113.100 17.995 113.430 18.455 ;
        RECT 113.940 17.995 114.270 18.455 ;
        RECT 114.780 17.995 115.110 18.455 ;
        RECT 115.620 17.995 115.950 18.455 ;
        RECT 120.320 18.455 126.530 18.645 ;
        RECT 120.320 17.995 120.650 18.455 ;
        RECT 121.160 17.995 121.490 18.455 ;
        RECT 122.000 17.995 122.330 18.455 ;
        RECT 122.840 17.995 123.170 18.455 ;
        RECT 123.680 17.995 124.010 18.455 ;
        RECT 124.520 17.995 124.850 18.455 ;
        RECT 125.360 17.995 125.690 18.455 ;
        RECT 126.200 17.995 126.530 18.455 ;
        RECT 130.900 18.455 137.110 18.645 ;
        RECT 130.900 17.995 131.230 18.455 ;
        RECT 131.740 17.995 132.070 18.455 ;
        RECT 132.580 17.995 132.910 18.455 ;
        RECT 133.420 17.995 133.750 18.455 ;
        RECT 134.260 17.995 134.590 18.455 ;
        RECT 135.100 17.995 135.430 18.455 ;
        RECT 135.940 17.995 136.270 18.455 ;
        RECT 136.780 17.995 137.110 18.455 ;
        RECT 88.580 10.665 88.910 11.465 ;
        RECT 89.420 10.665 89.750 11.465 ;
        RECT 90.260 10.665 90.590 11.465 ;
        RECT 91.100 10.665 91.430 11.465 ;
        RECT 91.940 10.665 92.270 11.465 ;
        RECT 92.780 10.665 93.110 11.465 ;
        RECT 93.620 10.665 93.950 11.465 ;
        RECT 94.460 10.665 94.790 11.465 ;
        RECT 88.580 10.495 94.790 10.665 ;
        RECT 99.160 10.665 99.490 11.465 ;
        RECT 100.000 10.665 100.330 11.465 ;
        RECT 100.840 10.665 101.170 11.465 ;
        RECT 101.680 10.665 102.010 11.465 ;
        RECT 102.520 10.665 102.850 11.465 ;
        RECT 103.360 10.665 103.690 11.465 ;
        RECT 104.200 10.665 104.530 11.465 ;
        RECT 105.040 10.665 105.370 11.465 ;
        RECT 99.160 10.495 105.370 10.665 ;
        RECT 109.740 10.665 110.070 11.465 ;
        RECT 110.580 10.665 110.910 11.465 ;
        RECT 111.420 10.665 111.750 11.465 ;
        RECT 112.260 10.665 112.590 11.465 ;
        RECT 113.100 10.665 113.430 11.465 ;
        RECT 113.940 10.665 114.270 11.465 ;
        RECT 114.780 10.665 115.110 11.465 ;
        RECT 115.620 10.665 115.950 11.465 ;
        RECT 109.740 10.495 115.950 10.665 ;
        RECT 120.320 10.665 120.650 11.465 ;
        RECT 121.160 10.665 121.490 11.465 ;
        RECT 122.000 10.665 122.330 11.465 ;
        RECT 122.840 10.665 123.170 11.465 ;
        RECT 123.680 10.665 124.010 11.465 ;
        RECT 124.520 10.665 124.850 11.465 ;
        RECT 125.360 10.665 125.690 11.465 ;
        RECT 126.200 10.665 126.530 11.465 ;
        RECT 120.320 10.495 126.530 10.665 ;
        RECT 94.460 9.905 94.790 10.495 ;
        RECT 105.040 9.905 105.370 10.495 ;
        RECT 115.620 9.905 115.950 10.495 ;
        RECT 119.825 10.075 125.265 10.315 ;
        RECT 126.200 9.905 126.530 10.495 ;
        RECT 130.405 10.075 135.845 10.315 ;
        RECT 88.580 9.715 94.790 9.905 ;
        RECT 88.580 9.255 88.910 9.715 ;
        RECT 89.420 9.255 89.750 9.715 ;
        RECT 90.260 9.255 90.590 9.715 ;
        RECT 91.100 9.255 91.430 9.715 ;
        RECT 91.940 9.255 92.270 9.715 ;
        RECT 92.780 9.255 93.110 9.715 ;
        RECT 93.620 9.255 93.950 9.715 ;
        RECT 94.460 9.255 94.790 9.715 ;
        RECT 99.160 9.715 105.370 9.905 ;
        RECT 99.160 9.255 99.490 9.715 ;
        RECT 100.000 9.255 100.330 9.715 ;
        RECT 100.840 9.255 101.170 9.715 ;
        RECT 101.680 9.255 102.010 9.715 ;
        RECT 102.520 9.255 102.850 9.715 ;
        RECT 103.360 9.255 103.690 9.715 ;
        RECT 104.200 9.255 104.530 9.715 ;
        RECT 105.040 9.255 105.370 9.715 ;
        RECT 109.740 9.715 115.950 9.905 ;
        RECT 109.740 9.255 110.070 9.715 ;
        RECT 110.580 9.255 110.910 9.715 ;
        RECT 111.420 9.255 111.750 9.715 ;
        RECT 112.260 9.255 112.590 9.715 ;
        RECT 113.100 9.255 113.430 9.715 ;
        RECT 113.940 9.255 114.270 9.715 ;
        RECT 114.780 9.255 115.110 9.715 ;
        RECT 115.620 9.255 115.950 9.715 ;
        RECT 120.320 9.715 126.530 9.905 ;
        RECT 120.320 9.255 120.650 9.715 ;
        RECT 121.160 9.255 121.490 9.715 ;
        RECT 122.000 9.255 122.330 9.715 ;
        RECT 122.840 9.255 123.170 9.715 ;
        RECT 123.680 9.255 124.010 9.715 ;
        RECT 124.520 9.255 124.850 9.715 ;
        RECT 125.360 9.255 125.690 9.715 ;
        RECT 126.200 9.255 126.530 9.715 ;
      LAYER met1 ;
        RECT 87.140 27.795 87.580 27.890 ;
        RECT 96.240 27.795 96.680 27.890 ;
        RECT 87.140 27.545 88.380 27.795 ;
        RECT 94.520 27.545 96.680 27.795 ;
        RECT 87.140 27.450 87.580 27.545 ;
        RECT 96.240 27.450 96.680 27.545 ;
        RECT 97.720 27.795 98.160 27.890 ;
        RECT 106.820 27.795 107.260 27.890 ;
        RECT 97.720 27.545 98.960 27.795 ;
        RECT 105.100 27.545 107.260 27.795 ;
        RECT 97.720 27.450 98.160 27.545 ;
        RECT 106.820 27.450 107.260 27.545 ;
        RECT 108.300 27.795 108.740 27.890 ;
        RECT 117.400 27.795 117.840 27.890 ;
        RECT 108.300 27.545 109.540 27.795 ;
        RECT 115.680 27.545 117.840 27.795 ;
        RECT 108.300 27.450 108.740 27.545 ;
        RECT 117.400 27.450 117.840 27.545 ;
        RECT 118.880 27.795 119.320 27.890 ;
        RECT 127.980 27.795 128.420 27.890 ;
        RECT 118.880 27.545 120.120 27.795 ;
        RECT 126.260 27.545 128.420 27.795 ;
        RECT 118.880 27.450 119.320 27.545 ;
        RECT 127.980 27.450 128.420 27.545 ;
        RECT 129.460 27.795 129.900 27.890 ;
        RECT 138.560 27.795 139.000 27.890 ;
        RECT 129.460 27.545 130.700 27.795 ;
        RECT 136.840 27.545 139.000 27.795 ;
        RECT 129.460 27.450 129.900 27.545 ;
        RECT 138.560 27.450 139.000 27.545 ;
        RECT 87.140 19.055 87.580 19.150 ;
        RECT 96.240 19.055 96.680 19.150 ;
        RECT 87.140 18.805 88.380 19.055 ;
        RECT 94.520 18.805 96.680 19.055 ;
        RECT 87.140 18.710 87.580 18.805 ;
        RECT 96.240 18.710 96.680 18.805 ;
        RECT 97.720 19.055 98.160 19.150 ;
        RECT 106.820 19.055 107.260 19.150 ;
        RECT 97.720 18.805 98.960 19.055 ;
        RECT 105.100 18.805 107.260 19.055 ;
        RECT 97.720 18.710 98.160 18.805 ;
        RECT 106.820 18.710 107.260 18.805 ;
        RECT 108.300 19.055 108.740 19.150 ;
        RECT 117.400 19.055 117.840 19.150 ;
        RECT 108.300 18.805 109.540 19.055 ;
        RECT 115.680 18.805 117.840 19.055 ;
        RECT 108.300 18.710 108.740 18.805 ;
        RECT 117.400 18.710 117.840 18.805 ;
        RECT 118.880 19.055 119.320 19.150 ;
        RECT 127.980 19.055 128.420 19.150 ;
        RECT 118.880 18.805 120.120 19.055 ;
        RECT 126.260 18.805 128.420 19.055 ;
        RECT 118.880 18.710 119.320 18.805 ;
        RECT 127.980 18.710 128.420 18.805 ;
        RECT 129.460 19.055 129.900 19.150 ;
        RECT 138.560 19.055 139.000 19.150 ;
        RECT 129.460 18.805 130.700 19.055 ;
        RECT 136.840 18.805 139.000 19.055 ;
        RECT 129.460 18.710 129.900 18.805 ;
        RECT 138.560 18.710 139.000 18.805 ;
        RECT 96.240 10.315 96.680 10.410 ;
        RECT 106.820 10.315 107.260 10.410 ;
        RECT 117.400 10.315 117.840 10.410 ;
        RECT 94.520 10.065 96.680 10.315 ;
        RECT 105.100 10.065 107.260 10.315 ;
        RECT 115.680 10.065 117.840 10.315 ;
        RECT 96.240 9.970 96.680 10.065 ;
        RECT 106.820 9.970 107.260 10.065 ;
        RECT 117.400 9.970 117.840 10.065 ;
        RECT 118.880 10.315 119.320 10.410 ;
        RECT 127.980 10.315 128.420 10.410 ;
        RECT 118.880 10.065 120.120 10.315 ;
        RECT 126.260 10.065 128.420 10.315 ;
        RECT 118.880 9.970 119.320 10.065 ;
        RECT 127.980 9.970 128.420 10.065 ;
        RECT 129.460 10.315 129.900 10.410 ;
        RECT 129.460 10.065 130.700 10.315 ;
        RECT 129.460 9.970 129.900 10.065 ;
      LAYER met2 ;
        RECT 87.140 27.450 87.580 31.300 ;
        RECT 96.240 27.450 96.680 31.300 ;
        RECT 97.720 27.450 98.160 30.500 ;
        RECT 106.820 27.450 107.260 31.300 ;
        RECT 87.140 18.710 87.580 21.760 ;
        RECT 96.240 18.710 96.680 22.560 ;
        RECT 96.240 9.970 96.680 17.020 ;
        RECT 96.980 14.980 97.420 21.760 ;
        RECT 97.720 18.710 98.160 23.360 ;
        RECT 106.820 18.710 107.260 21.760 ;
        RECT 107.560 16.580 108.000 30.500 ;
        RECT 108.300 27.450 108.740 30.500 ;
        RECT 117.400 27.450 117.840 31.300 ;
        RECT 108.300 18.710 108.740 23.360 ;
        RECT 118.140 22.920 118.580 31.300 ;
        RECT 118.880 27.450 119.320 30.500 ;
        RECT 127.980 27.450 128.420 31.300 ;
        RECT 129.460 27.450 129.900 30.500 ;
        RECT 138.560 27.450 139.000 31.300 ;
        RECT 117.400 18.710 117.840 21.760 ;
        RECT 118.880 18.710 119.320 23.360 ;
        RECT 127.980 18.710 128.420 21.760 ;
        RECT 129.460 18.710 129.900 23.360 ;
        RECT 138.560 18.710 139.000 21.760 ;
        RECT 106.820 9.970 107.260 15.420 ;
        RECT 117.400 9.970 117.840 13.820 ;
        RECT 118.880 9.970 119.320 15.420 ;
        RECT 127.980 9.970 128.420 13.820 ;
        RECT 129.460 9.970 129.900 13.820 ;
      LAYER met3 ;
        RECT 87.120 30.860 139.020 31.300 ;
        RECT 97.700 30.060 129.920 30.500 ;
        RECT 97.700 22.920 129.920 23.360 ;
        RECT 96.220 22.120 108.020 22.560 ;
        RECT 87.120 21.320 139.020 21.760 ;
        RECT 96.220 16.580 108.020 17.020 ;
        RECT 96.960 14.980 119.340 15.420 ;
        RECT 117.380 13.380 129.920 13.820 ;
  END
END tt_um_regulated_pump
END LIBRARY

